VERSION 5.7 ;
  NOWIREEXTENSIONATPIN ON ;
  DIVIDERCHAR "/" ;
  BUSBITCHARS "[]" ;
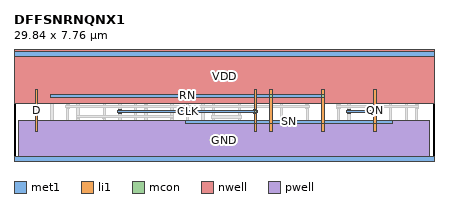
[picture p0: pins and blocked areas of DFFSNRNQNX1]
MACRO DFFSNRNQNX1
  CLASS CORE ;
  FOREIGN DFFSNRNQNX1 ;
  ORIGIN 0.000 0.000 ;
  SIZE 29.840 BY 7.760 ;
  SYMMETRY X Y ;
  SITE unitrh ;
  PIN QN
    DIRECTION OUTPUT ;
    USE SIGNAL ;
    ANTENNAGATEAREA 1.033250 ;
    ANTENNADIFFAREA 1.931900 ;
    PORT
      LAYER met1 ;
        RECT 23.685 3.595 23.915 3.625 ;
        RECT 25.535 3.595 25.765 3.625 ;
        RECT 23.655 3.425 25.795 3.595 ;
        RECT 23.685 3.395 23.915 3.425 ;
        RECT 25.535 3.395 25.765 3.425 ;
    END
    PORT
      LAYER li1 ;
        RECT 25.565 2.095 25.735 5.045 ;
      LAYER mcon ;
        RECT 25.565 3.425 25.735 3.595 ;
    END
  END QN
  PIN D
    DIRECTION INPUT ;
    USE SIGNAL ;
    ANTENNAGATEAREA 1.033250 ;
    PORT
      LAYER li1 ;
        RECT 1.515 2.095 1.685 5.045 ;
    END
  END D
  PIN CLK
    DIRECTION INPUT ;
    USE SIGNAL ;
    ANTENNAGATEAREA 2.029700 ;
    PORT
      LAYER met1 ;
        RECT 7.405 3.595 7.635 3.625 ;
        RECT 17.025 3.595 17.255 3.625 ;
        RECT 7.375 3.425 17.285 3.595 ;
        RECT 7.405 3.395 7.635 3.425 ;
        RECT 17.025 3.395 17.255 3.425 ;
    END
    PORT
      LAYER li1 ;
        RECT 17.055 2.095 17.225 5.045 ;
      LAYER mcon ;
        RECT 17.055 3.425 17.225 3.595 ;
    END
  END CLK
  PIN SN
    DIRECTION INPUT ;
    USE SIGNAL ;
    ANTENNAGATEAREA 2.029700 ;
    PORT
      LAYER met1 ;
        RECT 12.215 2.860 12.445 2.890 ;
        RECT 12.185 2.855 12.595 2.860 ;
        RECT 26.645 2.855 26.875 2.885 ;
        RECT 12.185 2.690 26.905 2.855 ;
        RECT 12.215 2.660 12.445 2.690 ;
        RECT 12.595 2.685 26.905 2.690 ;
        RECT 26.645 2.655 26.875 2.685 ;
    END
  END SN
  PIN RN
    DIRECTION INPUT ;
    USE SIGNAL ;
    ANTENNAGATEAREA 3.056950 ;
    PORT
      LAYER met1 ;
        RECT 2.595 4.705 2.825 4.735 ;
        RECT 18.135 4.705 18.365 4.735 ;
        RECT 21.835 4.705 22.065 4.735 ;
        RECT 2.565 4.535 22.095 4.705 ;
        RECT 2.595 4.505 2.825 4.535 ;
        RECT 18.135 4.505 18.365 4.535 ;
        RECT 21.835 4.505 22.065 4.535 ;
    END
    PORT
      LAYER li1 ;
        RECT 18.165 2.095 18.335 5.045 ;
      LAYER mcon ;
        RECT 18.165 4.535 18.335 4.705 ;
    END
    PORT
      LAYER li1 ;
        RECT 21.865 2.095 22.035 5.045 ;
      LAYER mcon ;
        RECT 21.865 4.535 22.035 4.705 ;
    END
  END RN
  PIN VDD
    DIRECTION INOUT ;
    USE POWER ;
    SHAPE ABUTMENT ;
    PORT
      LAYER nwell ;
        RECT 0.000 4.110 29.840 7.940 ;
      LAYER met1 ;
        RECT 0.000 7.410 29.840 7.760 ;
    END
  END VDD
  PIN GND
    DIRECTION INOUT ;
    USE GROUND ;
    SHAPE ABUTMENT ;
    PORT
      LAYER pwell ;
        RECT 0.320 0.000 29.520 2.900 ;
      LAYER met1 ;
        RECT 0.000 0.000 29.840 0.350 ;
    END
  END GND
  OBS
      LAYER li1 ;
        RECT 0.000 7.410 29.840 7.760 ;
        RECT 0.320 4.290 0.660 7.410 ;
        RECT 1.495 5.395 1.665 7.410 ;
        RECT 1.935 5.420 2.105 7.200 ;
        RECT 2.375 5.735 2.545 7.410 ;
        RECT 2.815 5.420 2.985 7.200 ;
        RECT 3.255 5.735 3.425 7.410 ;
        RECT 3.695 5.420 3.865 7.200 ;
        RECT 4.135 5.735 4.305 7.410 ;
        RECT 1.935 5.250 4.645 5.420 ;
        RECT 0.320 0.350 0.660 2.900 ;
        RECT 2.625 2.095 2.795 5.045 ;
        RECT 3.735 2.095 3.905 5.045 ;
        RECT 0.995 1.855 1.165 1.935 ;
        RECT 1.965 1.855 2.135 1.935 ;
        RECT 2.935 1.855 3.105 1.935 ;
        RECT 0.995 1.685 3.105 1.855 ;
        RECT 0.995 0.555 1.165 1.685 ;
        RECT 1.480 0.350 1.650 1.310 ;
        RECT 1.965 0.805 2.135 1.685 ;
        RECT 2.935 1.605 3.105 1.685 ;
        RECT 2.455 1.260 2.625 1.340 ;
        RECT 3.505 1.260 3.675 1.935 ;
        RECT 4.475 1.930 4.645 5.250 ;
        RECT 5.130 4.290 5.470 7.410 ;
        RECT 6.305 5.395 6.475 7.410 ;
        RECT 6.745 5.420 6.915 7.200 ;
        RECT 7.185 5.735 7.355 7.410 ;
        RECT 7.625 5.420 7.795 7.200 ;
        RECT 8.065 5.735 8.235 7.410 ;
        RECT 8.505 5.420 8.675 7.200 ;
        RECT 8.945 5.735 9.115 7.410 ;
        RECT 6.745 5.250 9.455 5.420 ;
        RECT 2.455 1.090 3.675 1.260 ;
        RECT 2.455 1.010 2.625 1.090 ;
        RECT 2.935 0.805 3.105 0.885 ;
        RECT 1.965 0.635 3.105 0.805 ;
        RECT 1.965 0.555 2.135 0.635 ;
        RECT 2.935 0.555 3.105 0.635 ;
        RECT 3.505 0.805 3.675 1.090 ;
        RECT 3.990 1.760 4.645 1.930 ;
        RECT 3.990 1.025 4.160 1.760 ;
        RECT 4.475 0.805 4.645 1.575 ;
        RECT 3.505 0.635 4.645 0.805 ;
        RECT 3.505 0.555 3.675 0.635 ;
        RECT 4.475 0.555 4.645 0.635 ;
        RECT 5.130 0.350 5.470 2.900 ;
        RECT 6.325 2.095 6.495 5.045 ;
        RECT 7.435 2.095 7.605 5.045 ;
        RECT 8.545 4.415 8.715 5.045 ;
        RECT 8.540 4.085 8.715 4.415 ;
        RECT 8.545 2.095 8.715 4.085 ;
        RECT 5.805 1.855 5.975 1.935 ;
        RECT 6.775 1.855 6.945 1.935 ;
        RECT 7.745 1.855 7.915 1.935 ;
        RECT 5.805 1.685 7.915 1.855 ;
        RECT 5.805 0.555 5.975 1.685 ;
        RECT 6.290 0.350 6.460 1.310 ;
        RECT 6.775 0.805 6.945 1.685 ;
        RECT 7.745 1.605 7.915 1.685 ;
        RECT 7.265 1.260 7.435 1.340 ;
        RECT 8.315 1.260 8.485 1.935 ;
        RECT 9.285 1.930 9.455 5.250 ;
        RECT 9.940 4.290 10.280 7.410 ;
        RECT 11.115 5.395 11.285 7.410 ;
        RECT 11.555 5.420 11.725 7.200 ;
        RECT 11.995 5.735 12.165 7.410 ;
        RECT 12.435 5.420 12.605 7.200 ;
        RECT 12.875 5.735 13.045 7.410 ;
        RECT 13.315 5.420 13.485 7.200 ;
        RECT 13.755 5.735 13.925 7.410 ;
        RECT 11.555 5.250 14.265 5.420 ;
        RECT 7.265 1.090 8.485 1.260 ;
        RECT 7.265 1.010 7.435 1.090 ;
        RECT 7.745 0.805 7.915 0.885 ;
        RECT 6.775 0.635 7.915 0.805 ;
        RECT 6.775 0.555 6.945 0.635 ;
        RECT 7.745 0.555 7.915 0.635 ;
        RECT 8.315 0.805 8.485 1.090 ;
        RECT 8.800 1.760 9.455 1.930 ;
        RECT 8.800 1.025 8.970 1.760 ;
        RECT 9.285 0.805 9.455 1.575 ;
        RECT 8.315 0.635 9.455 0.805 ;
        RECT 8.315 0.555 8.485 0.635 ;
        RECT 9.285 0.555 9.455 0.635 ;
        RECT 9.940 0.350 10.280 2.900 ;
        RECT 11.135 2.095 11.305 5.045 ;
        RECT 12.245 2.095 12.415 5.045 ;
        RECT 13.355 2.095 13.525 5.045 ;
        RECT 10.615 1.855 10.785 1.935 ;
        RECT 11.585 1.855 11.755 1.935 ;
        RECT 12.555 1.855 12.725 1.935 ;
        RECT 10.615 1.685 12.725 1.855 ;
        RECT 10.615 0.555 10.785 1.685 ;
        RECT 11.100 0.350 11.270 1.310 ;
        RECT 11.585 0.805 11.755 1.685 ;
        RECT 12.555 1.605 12.725 1.685 ;
        RECT 12.075 1.260 12.245 1.340 ;
        RECT 13.125 1.260 13.295 1.935 ;
        RECT 14.095 1.930 14.265 5.250 ;
        RECT 14.750 4.290 15.090 7.410 ;
        RECT 15.925 5.395 16.095 7.410 ;
        RECT 16.365 5.420 16.535 7.200 ;
        RECT 16.805 5.735 16.975 7.410 ;
        RECT 17.245 5.420 17.415 7.200 ;
        RECT 17.685 5.735 17.855 7.410 ;
        RECT 18.125 5.420 18.295 7.200 ;
        RECT 18.565 5.735 18.735 7.410 ;
        RECT 16.365 5.250 19.075 5.420 ;
        RECT 12.075 1.090 13.295 1.260 ;
        RECT 12.075 1.010 12.245 1.090 ;
        RECT 12.555 0.805 12.725 0.885 ;
        RECT 11.585 0.635 12.725 0.805 ;
        RECT 11.585 0.555 11.755 0.635 ;
        RECT 12.555 0.555 12.725 0.635 ;
        RECT 13.125 0.805 13.295 1.090 ;
        RECT 13.610 1.760 14.265 1.930 ;
        RECT 13.610 1.025 13.780 1.760 ;
        RECT 14.095 0.805 14.265 1.575 ;
        RECT 13.125 0.635 14.265 0.805 ;
        RECT 13.125 0.555 13.295 0.635 ;
        RECT 14.095 0.555 14.265 0.635 ;
        RECT 14.750 0.350 15.090 2.900 ;
        RECT 15.945 2.095 16.115 5.045 ;
        RECT 15.425 1.855 15.595 1.935 ;
        RECT 16.395 1.855 16.565 1.935 ;
        RECT 17.365 1.855 17.535 1.935 ;
        RECT 15.425 1.685 17.535 1.855 ;
        RECT 15.425 0.555 15.595 1.685 ;
        RECT 15.910 0.350 16.080 1.310 ;
        RECT 16.395 0.805 16.565 1.685 ;
        RECT 17.365 1.605 17.535 1.685 ;
        RECT 16.885 1.260 17.055 1.340 ;
        RECT 17.935 1.260 18.105 1.935 ;
        RECT 18.905 1.930 19.075 5.250 ;
        RECT 19.560 4.290 19.900 7.410 ;
        RECT 20.735 5.395 20.905 7.410 ;
        RECT 21.175 5.420 21.345 7.200 ;
        RECT 21.615 5.735 21.785 7.410 ;
        RECT 22.055 5.420 22.225 7.200 ;
        RECT 22.495 5.735 22.665 7.410 ;
        RECT 22.935 5.420 23.105 7.200 ;
        RECT 23.375 5.735 23.545 7.410 ;
        RECT 21.175 5.250 23.885 5.420 ;
        RECT 16.885 1.090 18.105 1.260 ;
        RECT 16.885 1.010 17.055 1.090 ;
        RECT 17.365 0.805 17.535 0.885 ;
        RECT 16.395 0.635 17.535 0.805 ;
        RECT 16.395 0.555 16.565 0.635 ;
        RECT 17.365 0.555 17.535 0.635 ;
        RECT 17.935 0.805 18.105 1.090 ;
        RECT 18.420 1.760 19.075 1.930 ;
        RECT 18.420 1.025 18.590 1.760 ;
        RECT 18.905 0.805 19.075 1.575 ;
        RECT 17.935 0.635 19.075 0.805 ;
        RECT 17.935 0.555 18.105 0.635 ;
        RECT 18.905 0.555 19.075 0.635 ;
        RECT 19.560 0.350 19.900 2.900 ;
        RECT 20.755 2.095 20.925 5.045 ;
        RECT 22.975 2.095 23.145 5.045 ;
        RECT 20.235 1.855 20.405 1.935 ;
        RECT 21.205 1.855 21.375 1.935 ;
        RECT 22.175 1.855 22.345 1.935 ;
        RECT 20.235 1.685 22.345 1.855 ;
        RECT 20.235 0.555 20.405 1.685 ;
        RECT 20.720 0.350 20.890 1.310 ;
        RECT 21.205 0.805 21.375 1.685 ;
        RECT 22.175 1.605 22.345 1.685 ;
        RECT 21.695 1.260 21.865 1.340 ;
        RECT 22.745 1.260 22.915 1.935 ;
        RECT 23.715 1.930 23.885 5.250 ;
        RECT 24.370 4.290 24.710 7.410 ;
        RECT 25.545 5.395 25.715 7.410 ;
        RECT 25.985 5.420 26.155 7.200 ;
        RECT 26.425 5.735 26.595 7.410 ;
        RECT 26.865 5.420 27.035 7.200 ;
        RECT 27.305 5.735 27.475 7.410 ;
        RECT 27.745 5.420 27.915 7.200 ;
        RECT 28.185 5.735 28.355 7.410 ;
        RECT 25.985 5.250 28.695 5.420 ;
        RECT 21.695 1.090 22.915 1.260 ;
        RECT 21.695 1.010 21.865 1.090 ;
        RECT 22.175 0.805 22.345 0.885 ;
        RECT 21.205 0.635 22.345 0.805 ;
        RECT 21.205 0.555 21.375 0.635 ;
        RECT 22.175 0.555 22.345 0.635 ;
        RECT 22.745 0.805 22.915 1.090 ;
        RECT 23.230 1.760 23.885 1.930 ;
        RECT 23.230 1.025 23.400 1.760 ;
        RECT 23.715 0.805 23.885 1.575 ;
        RECT 22.745 0.635 23.885 0.805 ;
        RECT 22.745 0.555 22.915 0.635 ;
        RECT 23.715 0.555 23.885 0.635 ;
        RECT 24.370 0.350 24.710 2.900 ;
        RECT 26.675 2.095 26.845 5.045 ;
        RECT 27.785 2.095 27.955 5.045 ;
        RECT 25.045 1.855 25.215 1.935 ;
        RECT 26.015 1.855 26.185 1.935 ;
        RECT 26.985 1.855 27.155 1.935 ;
        RECT 25.045 1.685 27.155 1.855 ;
        RECT 25.045 0.555 25.215 1.685 ;
        RECT 25.530 0.350 25.700 1.310 ;
        RECT 26.015 0.805 26.185 1.685 ;
        RECT 26.985 1.605 27.155 1.685 ;
        RECT 26.505 1.260 26.675 1.340 ;
        RECT 27.555 1.260 27.725 1.935 ;
        RECT 28.525 1.930 28.695 5.250 ;
        RECT 29.180 4.290 29.520 7.410 ;
        RECT 26.505 1.090 27.725 1.260 ;
        RECT 26.505 1.010 26.675 1.090 ;
        RECT 26.985 0.805 27.155 0.885 ;
        RECT 26.015 0.635 27.155 0.805 ;
        RECT 26.015 0.555 26.185 0.635 ;
        RECT 26.985 0.555 27.155 0.635 ;
        RECT 27.555 0.805 27.725 1.090 ;
        RECT 28.040 1.760 28.695 1.930 ;
        RECT 28.040 1.025 28.210 1.760 ;
        RECT 28.525 0.805 28.695 1.575 ;
        RECT 27.555 0.635 28.695 0.805 ;
        RECT 27.555 0.555 27.725 0.635 ;
        RECT 28.525 0.555 28.695 0.635 ;
        RECT 29.180 0.350 29.520 2.900 ;
        RECT 0.000 0.000 29.840 0.350 ;
      LAYER mcon ;
        RECT 0.775 7.495 0.945 7.665 ;
        RECT 1.145 7.495 1.315 7.665 ;
        RECT 1.515 7.495 1.685 7.665 ;
        RECT 1.885 7.495 2.055 7.665 ;
        RECT 2.255 7.495 2.425 7.665 ;
        RECT 2.625 7.495 2.795 7.665 ;
        RECT 2.995 7.495 3.165 7.665 ;
        RECT 3.365 7.495 3.535 7.665 ;
        RECT 3.735 7.495 3.905 7.665 ;
        RECT 4.105 7.495 4.275 7.665 ;
        RECT 4.475 7.495 4.645 7.665 ;
        RECT 4.845 7.495 5.015 7.665 ;
        RECT 5.585 7.495 5.755 7.665 ;
        RECT 5.955 7.495 6.125 7.665 ;
        RECT 6.325 7.495 6.495 7.665 ;
        RECT 6.695 7.495 6.865 7.665 ;
        RECT 7.065 7.495 7.235 7.665 ;
        RECT 7.435 7.495 7.605 7.665 ;
        RECT 7.805 7.495 7.975 7.665 ;
        RECT 8.175 7.495 8.345 7.665 ;
        RECT 8.545 7.495 8.715 7.665 ;
        RECT 8.915 7.495 9.085 7.665 ;
        RECT 9.285 7.495 9.455 7.665 ;
        RECT 9.655 7.495 9.825 7.665 ;
        RECT 10.395 7.495 10.565 7.665 ;
        RECT 10.765 7.495 10.935 7.665 ;
        RECT 11.135 7.495 11.305 7.665 ;
        RECT 11.505 7.495 11.675 7.665 ;
        RECT 11.875 7.495 12.045 7.665 ;
        RECT 12.245 7.495 12.415 7.665 ;
        RECT 12.615 7.495 12.785 7.665 ;
        RECT 12.985 7.495 13.155 7.665 ;
        RECT 13.355 7.495 13.525 7.665 ;
        RECT 13.725 7.495 13.895 7.665 ;
        RECT 14.095 7.495 14.265 7.665 ;
        RECT 14.465 7.495 14.635 7.665 ;
        RECT 15.205 7.495 15.375 7.665 ;
        RECT 15.575 7.495 15.745 7.665 ;
        RECT 15.945 7.495 16.115 7.665 ;
        RECT 16.315 7.495 16.485 7.665 ;
        RECT 16.685 7.495 16.855 7.665 ;
        RECT 17.055 7.495 17.225 7.665 ;
        RECT 17.425 7.495 17.595 7.665 ;
        RECT 17.795 7.495 17.965 7.665 ;
        RECT 18.165 7.495 18.335 7.665 ;
        RECT 18.535 7.495 18.705 7.665 ;
        RECT 18.905 7.495 19.075 7.665 ;
        RECT 19.275 7.495 19.445 7.665 ;
        RECT 20.015 7.495 20.185 7.665 ;
        RECT 20.385 7.495 20.555 7.665 ;
        RECT 20.755 7.495 20.925 7.665 ;
        RECT 21.125 7.495 21.295 7.665 ;
        RECT 21.495 7.495 21.665 7.665 ;
        RECT 21.865 7.495 22.035 7.665 ;
        RECT 22.235 7.495 22.405 7.665 ;
        RECT 22.605 7.495 22.775 7.665 ;
        RECT 22.975 7.495 23.145 7.665 ;
        RECT 23.345 7.495 23.515 7.665 ;
        RECT 23.715 7.495 23.885 7.665 ;
        RECT 24.085 7.495 24.255 7.665 ;
        RECT 24.825 7.495 24.995 7.665 ;
        RECT 25.195 7.495 25.365 7.665 ;
        RECT 25.565 7.495 25.735 7.665 ;
        RECT 25.935 7.495 26.105 7.665 ;
        RECT 26.305 7.495 26.475 7.665 ;
        RECT 26.675 7.495 26.845 7.665 ;
        RECT 27.045 7.495 27.215 7.665 ;
        RECT 27.415 7.495 27.585 7.665 ;
        RECT 27.785 7.495 27.955 7.665 ;
        RECT 28.155 7.495 28.325 7.665 ;
        RECT 28.525 7.495 28.695 7.665 ;
        RECT 28.895 7.495 29.065 7.665 ;
        RECT 2.625 4.535 2.795 4.705 ;
        RECT 3.735 3.795 3.905 3.965 ;
        RECT 4.475 3.060 4.645 3.230 ;
        RECT 6.325 3.060 6.495 3.230 ;
        RECT 8.540 4.165 8.710 4.335 ;
        RECT 7.435 3.425 7.605 3.595 ;
        RECT 9.285 3.795 9.455 3.965 ;
        RECT 11.135 3.060 11.305 3.230 ;
        RECT 12.245 2.690 12.415 2.860 ;
        RECT 13.355 4.165 13.525 4.335 ;
        RECT 14.095 3.055 14.265 3.225 ;
        RECT 15.945 3.055 16.115 3.225 ;
        RECT 18.905 4.165 19.075 4.335 ;
        RECT 20.755 3.795 20.925 3.965 ;
        RECT 22.975 3.795 23.145 3.965 ;
        RECT 23.715 3.425 23.885 3.595 ;
        RECT 26.675 2.685 26.845 2.855 ;
        RECT 27.785 4.165 27.955 4.335 ;
        RECT 28.525 3.795 28.695 3.965 ;
        RECT 0.775 0.095 0.945 0.265 ;
        RECT 1.145 0.095 1.315 0.265 ;
        RECT 1.515 0.095 1.685 0.265 ;
        RECT 1.885 0.095 2.055 0.265 ;
        RECT 2.255 0.095 2.425 0.265 ;
        RECT 2.625 0.095 2.795 0.265 ;
        RECT 2.995 0.095 3.165 0.265 ;
        RECT 3.365 0.095 3.535 0.265 ;
        RECT 3.735 0.095 3.905 0.265 ;
        RECT 4.105 0.095 4.275 0.265 ;
        RECT 4.475 0.095 4.645 0.265 ;
        RECT 4.845 0.095 5.015 0.265 ;
        RECT 5.585 0.095 5.755 0.265 ;
        RECT 5.955 0.095 6.125 0.265 ;
        RECT 6.325 0.095 6.495 0.265 ;
        RECT 6.695 0.095 6.865 0.265 ;
        RECT 7.065 0.095 7.235 0.265 ;
        RECT 7.435 0.095 7.605 0.265 ;
        RECT 7.805 0.095 7.975 0.265 ;
        RECT 8.175 0.095 8.345 0.265 ;
        RECT 8.545 0.095 8.715 0.265 ;
        RECT 8.915 0.095 9.085 0.265 ;
        RECT 9.285 0.095 9.455 0.265 ;
        RECT 9.655 0.095 9.825 0.265 ;
        RECT 10.395 0.095 10.565 0.265 ;
        RECT 10.765 0.095 10.935 0.265 ;
        RECT 11.135 0.095 11.305 0.265 ;
        RECT 11.505 0.095 11.675 0.265 ;
        RECT 11.875 0.095 12.045 0.265 ;
        RECT 12.245 0.095 12.415 0.265 ;
        RECT 12.615 0.095 12.785 0.265 ;
        RECT 12.985 0.095 13.155 0.265 ;
        RECT 13.355 0.095 13.525 0.265 ;
        RECT 13.725 0.095 13.895 0.265 ;
        RECT 14.095 0.095 14.265 0.265 ;
        RECT 14.465 0.095 14.635 0.265 ;
        RECT 15.205 0.095 15.375 0.265 ;
        RECT 15.575 0.095 15.745 0.265 ;
        RECT 15.945 0.095 16.115 0.265 ;
        RECT 16.315 0.095 16.485 0.265 ;
        RECT 16.685 0.095 16.855 0.265 ;
        RECT 17.055 0.095 17.225 0.265 ;
        RECT 17.425 0.095 17.595 0.265 ;
        RECT 17.795 0.095 17.965 0.265 ;
        RECT 18.165 0.095 18.335 0.265 ;
        RECT 18.535 0.095 18.705 0.265 ;
        RECT 18.905 0.095 19.075 0.265 ;
        RECT 19.275 0.095 19.445 0.265 ;
        RECT 20.015 0.095 20.185 0.265 ;
        RECT 20.385 0.095 20.555 0.265 ;
        RECT 20.755 0.095 20.925 0.265 ;
        RECT 21.125 0.095 21.295 0.265 ;
        RECT 21.495 0.095 21.665 0.265 ;
        RECT 21.865 0.095 22.035 0.265 ;
        RECT 22.235 0.095 22.405 0.265 ;
        RECT 22.605 0.095 22.775 0.265 ;
        RECT 22.975 0.095 23.145 0.265 ;
        RECT 23.345 0.095 23.515 0.265 ;
        RECT 23.715 0.095 23.885 0.265 ;
        RECT 24.085 0.095 24.255 0.265 ;
        RECT 24.825 0.095 24.995 0.265 ;
        RECT 25.195 0.095 25.365 0.265 ;
        RECT 25.565 0.095 25.735 0.265 ;
        RECT 25.935 0.095 26.105 0.265 ;
        RECT 26.305 0.095 26.475 0.265 ;
        RECT 26.675 0.095 26.845 0.265 ;
        RECT 27.045 0.095 27.215 0.265 ;
        RECT 27.415 0.095 27.585 0.265 ;
        RECT 27.785 0.095 27.955 0.265 ;
        RECT 28.155 0.095 28.325 0.265 ;
        RECT 28.525 0.095 28.695 0.265 ;
        RECT 28.895 0.095 29.065 0.265 ;
      LAYER met1 ;
        RECT 8.510 4.335 8.740 4.365 ;
        RECT 13.325 4.335 13.555 4.365 ;
        RECT 18.875 4.335 19.105 4.365 ;
        RECT 27.755 4.335 27.985 4.365 ;
        RECT 8.480 4.165 28.015 4.335 ;
        RECT 8.510 4.135 8.740 4.165 ;
        RECT 13.325 4.135 13.555 4.165 ;
        RECT 18.875 4.135 19.105 4.165 ;
        RECT 27.755 4.135 27.985 4.165 ;
        RECT 3.705 3.965 3.935 3.995 ;
        RECT 9.255 3.965 9.485 3.995 ;
        RECT 20.725 3.965 20.955 3.995 ;
        RECT 22.945 3.965 23.175 3.995 ;
        RECT 28.495 3.965 28.725 3.995 ;
        RECT 3.675 3.795 20.985 3.965 ;
        RECT 22.915 3.795 28.755 3.965 ;
        RECT 3.705 3.765 3.935 3.795 ;
        RECT 9.255 3.765 9.485 3.795 ;
        RECT 20.725 3.765 20.955 3.795 ;
        RECT 22.945 3.765 23.175 3.795 ;
        RECT 28.495 3.765 28.725 3.795 ;
        RECT 4.445 3.230 4.675 3.260 ;
        RECT 6.295 3.230 6.525 3.260 ;
        RECT 11.105 3.230 11.335 3.260 ;
        RECT 4.415 3.060 11.365 3.230 ;
        RECT 14.065 3.225 14.295 3.255 ;
        RECT 15.915 3.225 16.145 3.255 ;
        RECT 4.445 3.030 4.675 3.060 ;
        RECT 6.295 3.030 6.525 3.060 ;
        RECT 11.105 3.030 11.335 3.060 ;
        RECT 14.035 3.055 16.175 3.225 ;
        RECT 14.065 3.025 14.295 3.055 ;
        RECT 15.915 3.025 16.145 3.055 ;
  END
END DFFSNRNQNX1
END LIBRARY

